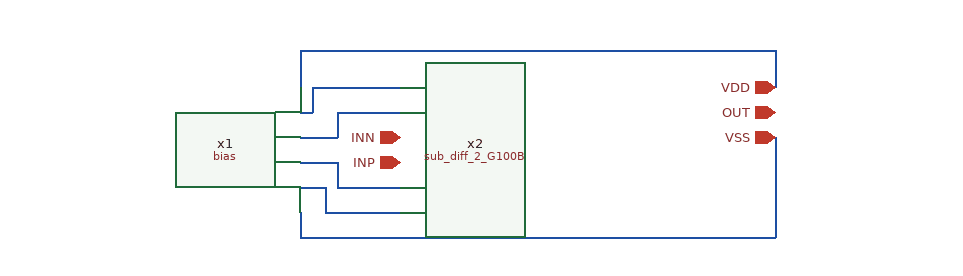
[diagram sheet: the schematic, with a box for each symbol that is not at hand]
v {xschem version=3.4.8RC file_version=1.3}
G {}
K {}
V {}
S {}
F {}
E {}
N 420 -510 440 -510 {lab=#net1}
N 440 -510 440 -490 {lab=#net1}
N 440 -490 500 -490 {lab=#net1}
N 460 -510 500 -510 {lab=#net2}
N 450 -510 460 -510 {lab=#net2}
N 450 -530 450 -510 {lab=#net2}
N 420 -530 450 -530 {lab=#net2}
N 420 -570 430 -570 {lab=#net3}
N 430 -590 430 -570 {lab=#net3}
N 430 -590 500 -590 {lab=#net3}
N 420 -550 450 -550 {lab=#net4}
N 450 -570 450 -550 {lab=#net4}
N 450 -570 500 -570 {lab=#net4}
N 420 -490 420 -470 {lab=VSS}
N 420 -470 790 -470 {lab=VSS}
N 790 -470 800 -470 {lab=VSS}
N 800 -550 800 -470 {lab=VSS}
N 800 -620 800 -590 {lab=VDD}
N 420 -620 800 -620 {lab=VDD}
N 420 -620 420 -590 {lab=VDD}
C {ipin.sym} 500 -550 0 0 {name=p1 lab=INN}
C {ipin.sym} 500 -530 0 0 {name=p2 lab=INP}
C {iopin.sym} 800 -590 0 0 {name=p3 lab=VDD}
C {iopin.sym} 800 -550 0 0 {name=p4 lab=VSS}
C {iopin.sym} 800 -570 0 0 {name=p5 lab=OUT}
C {a_zonetic2026/XSCHEM/OPAM/bias.sym} 270 -540 0 0 {name=x1}
C {a_zonetic2026/XSCHEM/OPAM/sub_diff_2_G100B.sym} 650 -540 0 0 {name=x2}
